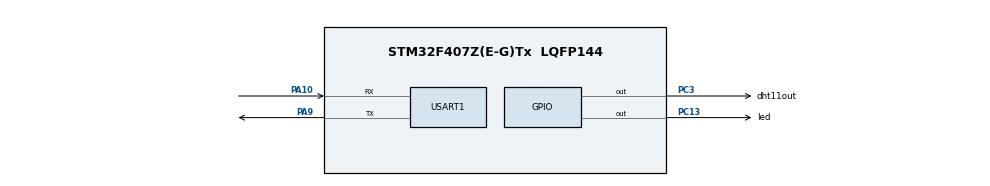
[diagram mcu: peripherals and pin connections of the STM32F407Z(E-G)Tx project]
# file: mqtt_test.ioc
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FREERTOS.Tasks01=defaultTask,24,128,StartDefaultTask,Default,NULL,Dynamic,NULL,NULL
Mcu.Family=STM32F4
Mcu.Name=STM32F407Z(E-G)Tx
Mcu.Package=LQFP144
NVIC.PriorityGroup=NVIC_PRIORITYGROUP_4
NVIC.TIM8_TRG_COM_TIM14_IRQn=true\:15\:0\:false\:false\:true\:false\:false\:true\:true
NVIC.TimeBase=TIM8_TRG_COM_TIM14_IRQn
NVIC.TimeBaseIP=TIM14
NVIC.USART1_IRQn=true\:5\:0\:false\:false\:true\:true\:true\:true\:true
PA10.Mode=Asynchronous
PA10.Signal=USART1_RX
PA13.Mode=Serial_Wire
PA13.Signal=SYS_JTMS-SWDIO
PA14.Mode=Serial_Wire
PA14.Signal=SYS_JTCK-SWCLK
PA9.Mode=Asynchronous
PA9.Signal=USART1_TX
PC13-ANTI_TAMP.GPIO_Label=led
PC13-ANTI_TAMP.Signal=GPIO_Output
PC3.GPIO_Label=dht11out
PC3.GPIO_ModeDefaultOutputPP=GPIO_MODE_OUTPUT_PP
PC3.GPIO_PuPd=GPIO_PULLUP
PC3.Signal=GPIO_Output
ProjectManager.HeapSize=0x200
ProjectManager.StackSize=0x400
ProjectManager.TargetToolchain=CMake
RCC.AHBFreq_Value=16000000
RCC.APB1Freq_Value=16000000
RCC.APB2Freq_Value=16000000
RCC.CortexFreq_Value=16000000
RCC.HSE_VALUE=25000000
RCC.HSI_VALUE=16000000
RCC.LSE_VALUE=32768
RCC.SYSCLKFreq_VALUE=16000000
RCC.VCOOutputFreq_Value=192000000
USART1.VirtualMode=VM_ASYNC
VP_FREERTOS_VS_CMSIS_V2.Mode=CMSIS_V2
VP_SYS_VS_tim14.Mode=TIM14
board=custom

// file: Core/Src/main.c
/* USER CODE BEGIN Header */
/**
  ******************************************************************************
  * @file           : main.c
  * @brief          : Main program body
  ******************************************************************************
  * @attention
  *
  * Copyright (c) 2026 STMicroelectronics.
  * All rights reserved.
  *
  * This software is licensed under terms that can be found in the LICENSE file
  * in the root directory of this software component.
  * If no LICENSE file comes with this software, it is provided AS-IS.
  *
  ******************************************************************************
  */
/* USER CODE END Header */
#include "main.h"
#include "cmsis_os.h"

UART_HandleTypeDef huart1;

/* Definitions for defaultTask */
osThreadId_t defaultTaskHandle;
const osThreadAttr_t defaultTask_attributes = {
  .name = "defaultTask",
  .stack_size = 128 * 4,
  .priority = (osPriority_t) osPriorityNormal,
};

void SystemClock_Config(void);
static void MX_GPIO_Init(void);
static void MX_USART1_UART_Init(void);
void StartDefaultTask(void *argument);

int main(void)
{

  /* MCU Configuration--------------------------------------------------------*/

  /* Reset of all peripherals, Initializes the Flash interface and the Systick. */
  HAL_Init();

  /* Configure the system clock */
  SystemClock_Config();

  /* Initialize all configured peripherals */
  MX_GPIO_Init();
  MX_USART1_UART_Init();

  /* Init scheduler */
  osKernelInitialize();

  /* Create the thread(s) */
  /* creation of defaultTask */
  defaultTaskHandle = osThreadNew(StartDefaultTask, NULL, &defaultTask_attributes);

  /* Start scheduler */
  osKernelStart();

  /* We should never get here as control is now taken by the scheduler */

  /* Infinite loop */
  while (1)
  {

  }
}

void SystemClock_Config(void)
{
  RCC_OscInitTypeDef RCC_OscInitStruct = {0};
  RCC_ClkInitTypeDef RCC_ClkInitStruct = {0};

  __HAL_RCC_PWR_CLK_ENABLE();
  __HAL_PWR_VOLTAGESCALING_CONFIG(PWR_REGULATOR_VOLTAGE_SCALE1);

  /* HSE=25MHz, PLL: /25 * 336 / 2 = 168MHz */
  RCC_OscInitStruct.OscillatorType = RCC_OSCILLATORTYPE_HSE;
  RCC_OscInitStruct.HSEState = RCC_HSE_ON;
  RCC_OscInitStruct.PLL.PLLState = RCC_PLL_ON;
  RCC_OscInitStruct.PLL.PLLSource = RCC_PLLSOURCE_HSE;
  RCC_OscInitStruct.PLL.PLLM = 25;
  RCC_OscInitStruct.PLL.PLLN = 336;
  RCC_OscInitStruct.PLL.PLLP = RCC_PLLP_DIV2;
  RCC_OscInitStruct.PLL.PLLQ = 7;
  if (HAL_RCC_OscConfig(&RCC_OscInitStruct) != HAL_OK)
  {
    Error_Handler();
  }

  /* SYSCLK=168MHz, HCLK=168MHz, APB1=42MHz, APB2=84MHz */
  RCC_ClkInitStruct.ClockType = RCC_CLOCKTYPE_HCLK | RCC_CLOCKTYPE_SYSCLK
                              | RCC_CLOCKTYPE_PCLK1 | RCC_CLOCKTYPE_PCLK2;
  RCC_ClkInitStruct.SYSCLKSource = RCC_SYSCLKSOURCE_PLLCLK;
  RCC_ClkInitStruct.AHBCLKDivider = RCC_SYSCLK_DIV1;
  RCC_ClkInitStruct.APB1CLKDivider = RCC_HCLK_DIV4;
  RCC_ClkInitStruct.APB2CLKDivider = RCC_HCLK_DIV2;

  if (HAL_RCC_ClockConfig(&RCC_ClkInitStruct, FLASH_LATENCY_5) != HAL_OK)
  {
    Error_Handler();
  }
}

static void MX_USART1_UART_Init(void)
{

  huart1.Instance = USART1;
  huart1.Init.BaudRate = 115200;
  huart1.Init.WordLength = UART_WORDLENGTH_8B;
  huart1.Init.StopBits = UART_STOPBITS_1;
  huart1.Init.Parity = UART_PARITY_NONE;
  huart1.Init.Mode = UART_MODE_TX_RX;
  huart1.Init.HwFlowCtl = UART_HWCONTROL_NONE;
  huart1.Init.OverSampling = UART_OVERSAMPLING_16;
  if (HAL_UART_Init(&huart1) != HAL_OK)
  {
    Error_Handler();
  }

}

static void MX_GPIO_Init(void)
{
  GPIO_InitTypeDef GPIO_InitStruct = {0};

  /* GPIO Ports Clock Enable */
  __HAL_RCC_GPIOC_CLK_ENABLE();
  __HAL_RCC_GPIOA_CLK_ENABLE();

  /*Configure GPIO pin Output Level */
  HAL_GPIO_WritePin(GPIOC, led_Pin|dht11out_Pin, GPIO_PIN_RESET);

  /*Configure GPIO pin : led_Pin */
  GPIO_InitStruct.Pin = led_Pin;
  GPIO_InitStruct.Mode = GPIO_MODE_OUTPUT_PP;
  GPIO_InitStruct.Pull = GPIO_NOPULL;
  GPIO_InitStruct.Speed = GPIO_SPEED_FREQ_LOW;
  HAL_GPIO_Init(led_GPIO_Port, &GPIO_InitStruct);

  /*Configure GPIO pin : dht11out_Pin */
  GPIO_InitStruct.Pin = dht11out_Pin;
  GPIO_InitStruct.Mode = GPIO_MODE_OUTPUT_PP;
  GPIO_InitStruct.Pull = GPIO_PULLUP;
  GPIO_InitStruct.Speed = GPIO_SPEED_FREQ_LOW;
  HAL_GPIO_Init(dht11out_GPIO_Port, &GPIO_InitStruct);

}

void StartDefaultTask(void *argument)
{
  /* USER CODE BEGIN 5 */
  for(;;)
  {
    HAL_GPIO_TogglePin(led_GPIO_Port, led_Pin);
    osDelay(500);
  }
  /* USER CODE END 5 */
}

void HAL_TIM_PeriodElapsedCallback(TIM_HandleTypeDef *htim)
{
  if (htim->Instance == TIM14)
  {
    HAL_IncTick();
  }
}

void Error_Handler(void)
{
  __disable_irq();
  while (1)
  {
  }
}
